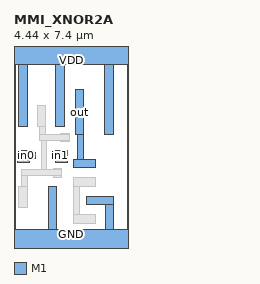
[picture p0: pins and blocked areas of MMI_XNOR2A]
MACRO MMI_XNOR2A
	CLASS CORE ;
	FOREIGN MMI_XNOR2A 0 0 ;
	SIZE 4.44 BY 7.4 ;
	SYMMETRY X Y ;
	SITE CORE1 ;
	PIN out
		DIRECTION output ;
		USE SIGNAL ;
		PORT
			LAYER M1 ;
			RECT 2.38 4.18 2.72 5.94 ;
			LAYER M1 ;
			RECT 2.47 3.23 2.7 4.18 ;
			LAYER M1 ;
			RECT 2.325 2.89 3.165 3.23 ;
		END
		AntennaDiffArea 1.4168 ;
	END out
	PIN in1
		DIRECTION input ;
		USE SIGNAL ;
		PORT
			LAYER M1 ;
			RECT 1.625 3.55 2.075 3.555 ;
			LAYER M1 ;
			RECT 1.515 3.21 2.075 3.55 ;
			LAYER M1 ;
			RECT 1.625 3.105 2.075 3.21 ;
		END
		AntennaGateArea 0.828 ;
	END in1
	PIN GND
		DIRECTION inout ;
		USE GROUND ;
		PORT
			LAYER M1 ;
			RECT 1.33 0.5 1.67 2.175 ;
			LAYER M1 ;
			RECT 2.825 1.45 3.885 1.79 ;
			LAYER M1 ;
			RECT 3.545 0.5 3.885 1.45 ;
			LAYER M1 ;
			RECT 0 -0.5 4.44 0.5 ;
		END
	END GND
	PIN VDD
		DIRECTION inout ;
		USE POWER ;
		PORT
			LAYER M1 ;
			RECT 0 6.9 4.44 7.9 ;
			LAYER M1 ;
			RECT 0.18 4.48 0.52 6.9 ;
			LAYER M1 ;
			RECT 1.62 4.48 1.96 6.9 ;
			LAYER M1 ;
			RECT 3.53 4.18 3.87 6.9 ;
		END
	END VDD
	PIN in0
		DIRECTION input ;
		USE SIGNAL ;
		PORT
			LAYER M1 ;
			RECT 0.145 3.55 0.595 3.555 ;
			LAYER M1 ;
			RECT 0.145 3.495 0.76 3.55 ;
			LAYER M1 ;
			RECT 0.145 3.265 0.825 3.495 ;
			LAYER M1 ;
			RECT 0.145 3.21 0.76 3.265 ;
			LAYER M1 ;
			RECT 0.145 3.105 0.595 3.21 ;
		END
		AntennaGateArea 0.828 ;
	END in0
	OBS
		LAYER M1 ;
		RECT 0.9 4.48 1.24 5.32 ;
		LAYER M1 ;
		RECT 1.01 4.185 1.24 4.48 ;
		LAYER M1 ;
		RECT 1.81 4.185 2.15 4.24 ;
		LAYER M1 ;
		RECT 1.01 3.955 2.15 4.185 ;
		LAYER M1 ;
		RECT 1.055 2.805 1.285 3.955 ;
		LAYER M1 ;
		RECT 1.81 3.9 2.15 3.955 ;
		LAYER M1 ;
		RECT 1.52 2.805 1.86 2.86 ;
		LAYER M1 ;
		RECT 0.29 2.575 1.86 2.805 ;
		LAYER M1 ;
		RECT 0.29 2.175 0.52 2.575 ;
		LAYER M1 ;
		RECT 1.52 2.52 1.86 2.575 ;
		LAYER M1 ;
		RECT 0.18 1.335 0.52 2.175 ;
		LAYER M1 ;
		RECT 2.325 2.17 3.165 2.51 ;
		LAYER M1 ;
		RECT 2.325 1.07 2.555 2.17 ;
		LAYER M1 ;
		RECT 2.325 0.73 3.165 1.07 ;
	END
END MMI_XNOR2A
